! (c) 2009  Infineon Technologies AG, Munich
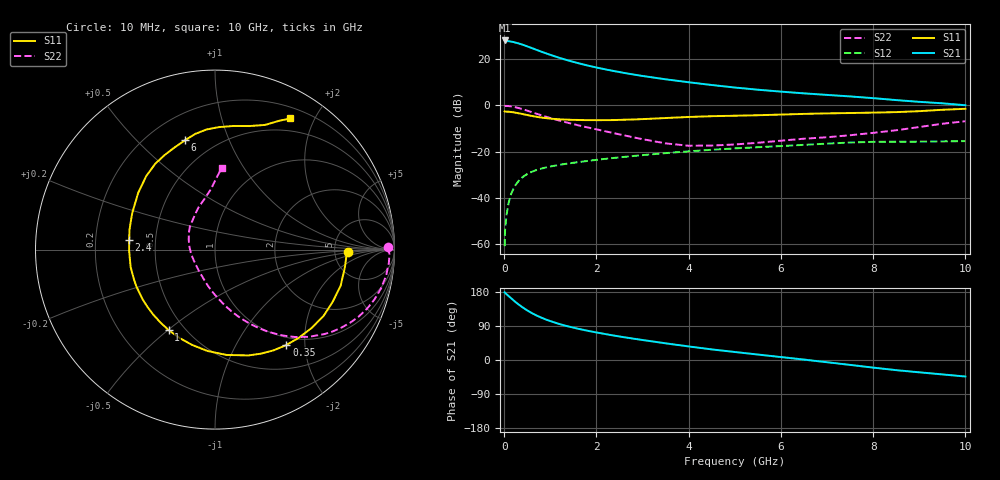
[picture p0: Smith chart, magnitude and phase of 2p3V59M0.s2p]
! Infineon Technologies  Discrete & RF Semiconductors
! BFP420
! VCE =  3.5 V,  IC =  9.0 mA
! Common Emitter S-Parameters:  Nov 2009
# GHz  S  MA  R  50
!  f  S11  S21  S12  S22
! GHz  MAG  ANG  MAG  ANG  MAG  ANG  MAG  ANG
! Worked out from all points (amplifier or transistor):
!   46 points, 10 MHz to 10 GHz, reference 50 ohm
!   highest |S21| = 28.1 dB at 10 MHz (marker M1)
!   |S21| within 3 dB of that: start of sweep to 560.2 MHz
!   unconditionally stable (mu >= 1): 2.469 GHz to end of sweep
!   at 300 MHz: K = 0.20, MSG = 30.0 dB, |S12| = -33.0 dB
!   at 1.7 GHz: K = 0.78, MSG = 21.1 dB, |S12| = -24.3 dB
!   at 10 GHz: K = 1.09, MAG = 5.9 dB, |S12| = -15.5 dB
!   S11 on the Smith chart (normalised r, x): 10 MHz: 6.77, -0.47; 350 MHz: 0.87, -1.65; 1 GHz: 0.41, -0.50; 2.4 GHz: 0.35, +0.05; 6 GHz: 0.35, +0.70; 10 GHz: 0.33, +1.68
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0.01  0.7436 -1.2  25.35 178.7  0.0009 80.2  0.9649 0.7
0.02  0.7327 -3.2  24.66 177.4  0.002 68.2  0.9722 -1.5
0.1  0.7284 -16.1  24.4 168.5  0.008 78.1  0.9641 -8.8
0.2  0.7088 -31.4  23.43 157.8  0.0156 73.3  0.9312 -17.3
0.3  0.6785 -46.2  22.06 147.8  0.0223 67.6  0.8832 -25.0
0.35  0.6638 -53.2  21.3 143.3  0.0252 65.0  0.8557 -28.5
0.4  0.6494 -59.8  20.5 138.9  0.028 62.5  0.8268 -31.8
0.5  0.6185 -72.4  18.89 130.9  0.0327 58.3  0.7687 -37.8
0.6  0.5903 -83.8  17.35 123.8  0.0366 54.6  0.7128 -43.0
0.7  0.5665 -94.2  15.9 117.6  0.0399 51.7  0.6606 -47.5
0.8  0.5462 -103.5  14.58 112.1  0.0427 49.3  0.6137 -51.4
1  0.5177 -119.9  12.4 102.7  0.0475 46.0  0.533 -58.1
1.3  0.4935 -139.6  9.938 91.5  0.0536 42.9  0.4408 -66.2
1.7  0.481 -159.9  7.746 80.0  0.0608 40.3  0.3524 -75.4
2.4  0.4814 173.5  5.474 64.1  0.0734 36.7  0.2479 -90.9
3.5  0.5319 143.6  3.664 44.0  0.0926 30.5  0.1505 -125.7
4.5  0.5829 124.8  2.755 28.0  0.1094 23.6  0.1352 -168.7
5.5  0.6118 111.7  2.18 14.4  0.1244 16.7  0.1552 160.4
6  0.632 105.3  1.983 7.8  0.1319 13.3  0.1722 147.9
7  0.6708 94.1  1.683 -5.9  0.1486 5.3  0.2045 127.9
8.5  0.7146 74.4  1.3 -26.8  0.1637 -10.2  0.2896 101.5
10  0.8432 60.1  1.005 -43.6  0.1685 -20.5  0.4541 85.4
